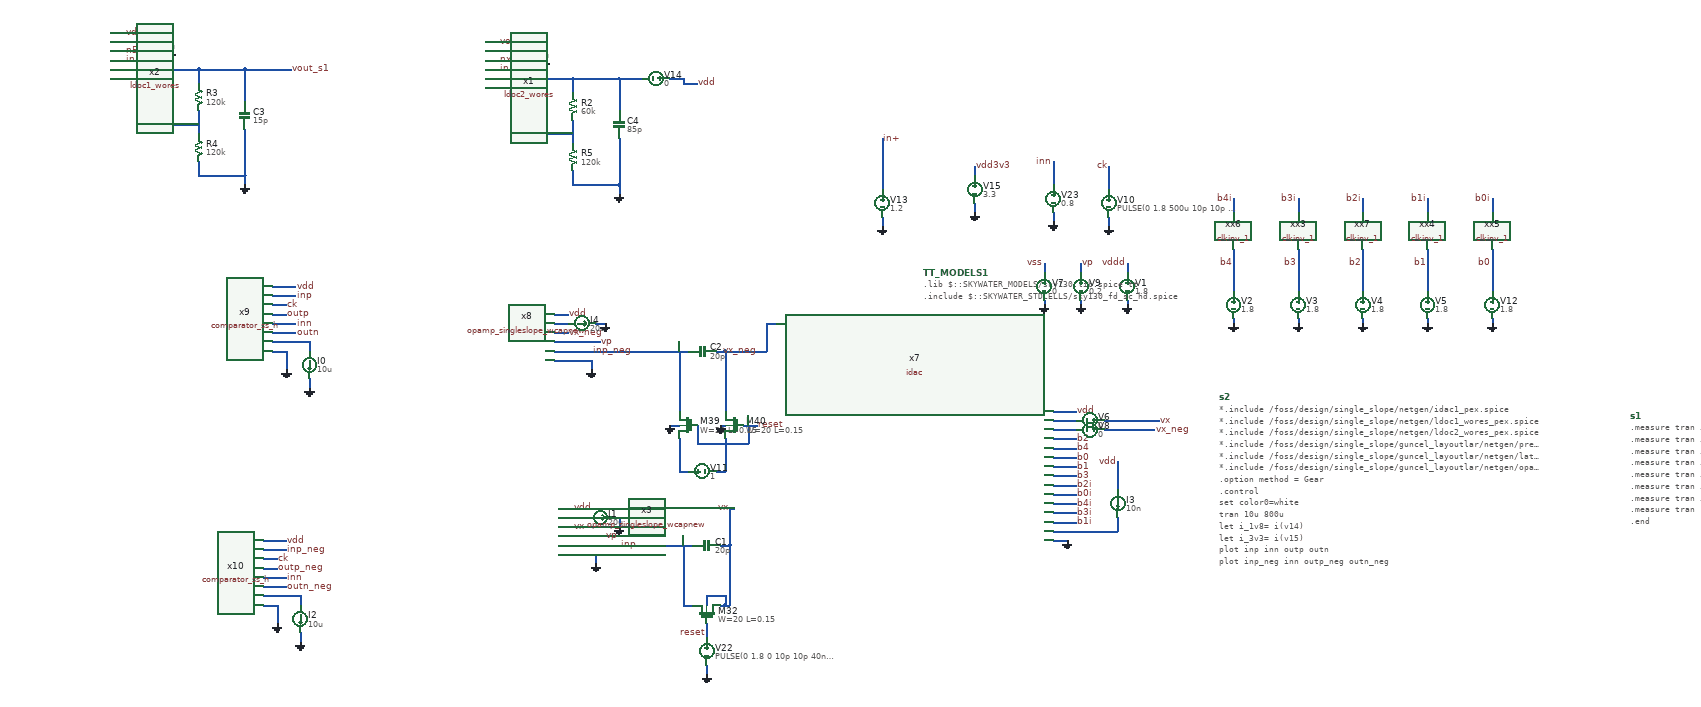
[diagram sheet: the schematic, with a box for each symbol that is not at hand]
v {xschem version=3.0.0 file_version=1.2 }
G {}
K {}
V {}
S {}
E {}
N 2600 -880 2600 -870 {
lab=GND}
N 2600 -960 2600 -940 {
lab=vddd}
N 2500 -880 2500 -870 {
lab=GND}
N 2500 -960 2500 -940 {
lab=vp}
N 2830 -990 2830 -960 {
lab=b4}
N 3250 -990 3250 -960 {
lab=b1}
N 3110 -990 3110 -960 {
lab=b2}
N 2970 -990 2970 -960 {
lab=b3}
N 3390 -990 3390 -960 {
lab=b0}
N 2830 -1100 2830 -1070 {
lab=b4i}
N 2970 -1100 2970 -1070 {
lab=b3i}
N 3110 -1100 3110 -1070 {
lab=b2i}
N 3250 -1100 3250 -1070 {
lab=b1i}
N 3390 -1100 3390 -1070 {
lab=b0i}
N 2420 -880 2420 -870 {
lab=GND}
N 2420 -960 2420 -940 {
lab=vss}
N 2830 -840 2830 -830 {
lab=GND}
N 2830 -910 2830 -900 {
lab=b4}
N 2970 -840 2970 -830 {
lab=GND}
N 3110 -840 3110 -830 {
lab=GND}
N 3250 -840 3250 -830 {
lab=GND}
N 3390 -840 3390 -830 {
lab=GND}
N 3110 -910 3110 -900 {
lab=b2}
N 2970 -910 2970 -900 {
lab=b3}
N 3390 -910 3390 -900 {
lab=b0}
N 3110 -920 3110 -910 {
lab=b2}
N 2970 -920 2970 -910 {
lab=b3}
N 3390 -920 3390 -910 {
lab=b0}
N 2830 -960 2830 -930 {
lab=b4}
N 3250 -960 3250 -930 {
lab=b1}
N 3110 -930 3110 -920 {
lab=b2}
N 2970 -930 2970 -920 {
lab=b3}
N 3110 -960 3110 -930 {
lab=b2}
N 2970 -960 2970 -930 {
lab=b3}
N 3390 -930 3390 -920 {
lab=b0}
N 3390 -960 3390 -930 {
lab=b0}
N 3250 -930 3250 -900 {
lab=b1}
N 2830 -930 2830 -910 {
lab=b4}
N 1720 -350 1740 -350 {
lab=vx}
N 1740 -430 1740 -350 {
lab=vx}
N 1580 -350 1660 -350 {
lab=inp}
N 1640 -220 1660 -220 {
lab=inp}
N 1640 -350 1640 -220 {
lab=inp}
N 1720 -220 1730 -220 {
lab=vx}
N 1730 -220 1740 -220 {
lab=vx}
N 1740 -350 1740 -220 {
lab=vx}
N 1690 -240 1690 -220 {
lab=vx}
N 1690 -240 1730 -240 {
lab=vx}
N 1730 -240 1730 -220 {
lab=vx}
N 1690 -180 1690 -150 {
lab=reset}
N 1690 -90 1690 -70 {
lab=GND}
N 1480 -350 1580 -350 {
lab=inp}
N 1370 -430 1400 -430 {
lab=vdd}
N 1370 -390 1400 -390 {
lab=vx}
N 1370 -370 1450 -370 {
lab=vp}
N 1370 -350 1390 -350 {
lab=inp}
N 1370 -330 1450 -330 {
lab=GND}
N 1450 -330 1450 -310 {
lab=GND}
N 1390 -350 1480 -350 {
lab=inp}
N 1450 -370 1470 -370 {
lab=vp}
N 1500 -410 1500 -390 {
lab=GND}
N 1370 -410 1430 -410 {
lab=#net1}
N 1490 -410 1500 -410 {
lab=GND}
N 1710 -770 1730 -770 {
lab=vx_neg}
N 1570 -770 1650 -770 {
lab=inp_neg}
N 1630 -770 1630 -640 {
lab=inp_neg}
N 1730 -770 1730 -640 {
lab=vx_neg}
N 1470 -770 1570 -770 {
lab=inp_neg}
N 1360 -830 1390 -830 {
lab=#net2}
N 1360 -810 1390 -810 {
lab=vx_neg}
N 1360 -790 1440 -790 {
lab=vp}
N 1360 -770 1380 -770 {
lab=inp_neg}
N 1360 -750 1440 -750 {
lab=GND}
N 1440 -750 1440 -730 {
lab=GND}
N 1380 -770 1470 -770 {
lab=inp_neg}
N 1440 -790 1460 -790 {
lab=vp}
N 1630 -510 1650 -510 {
lab=#net3}
N 1710 -510 1730 -510 {
lab=#net4}
N 1630 -580 1630 -510 {
lab=#net3}
N 1730 -580 1730 -510 {
lab=#net4}
N 1610 -610 1630 -610 {
lab=GND}
N 1720 -610 1730 -610 {
lab=GND}
N 1770 -610 1800 -610 {
lab=reset}
N 1670 -610 1670 -570 {
lab=reset}
N 1670 -570 1780 -570 {
lab=reset}
N 1780 -610 1780 -570 {
lab=reset}
N 1730 -770 1800 -770 {
lab=vx_neg}
N 1360 -850 1390 -850 {
lab=vdd}
N 1450 -830 1470 -830 {
lab=GND}
N 2440 -640 2490 -640 {
lab=vdd}
N 2440 -620 2490 -620 {
lab=#net5}
N 2440 -360 2470 -360 {
lab=GND}
N 2440 -580 2490 -580 {
lab=b2}
N 2440 -560 2490 -560 {
lab=b4}
N 2440 -540 2490 -540 {
lab=b0}
N 2440 -520 2490 -520 {
lab=b1}
N 2440 -500 2490 -500 {
lab=b3}
N 2440 -480 2490 -480 {
lab=b2i}
N 2440 -460 2490 -460 {
lab=b0i}
N 2440 -440 2490 -440 {
lab=b4i}
N 2440 -420 2490 -420 {
lab=b3i}
N 2440 -400 2490 -400 {
lab=b1i}
N 2440 -380 2490 -380 {
lab=#net6}
N 2580 -510 2580 -470 {
lab=vdd}
N 2580 -530 2580 -510 {
lab=vdd}
N 2490 -380 2580 -380 {
lab=#net6}
N 2560 -620 2590 -620 {
lab=vx}
N 2550 -620 2560 -620 {
lab=vx}
N 2550 -600 2590 -600 {
lab=vx_neg}
N 2440 -600 2490 -600 {
lab=#net7}
N 2560 -1060 2560 -1040 {
lab=GND}
N 2560 -1170 2560 -1120 {
lab=ck}
N 2440 -1070 2440 -1050 {
lab=GND}
N 2440 -1180 2440 -1130 {
lab=inn}
N 1740 -430 1750 -430 {
lab=vx}
N 1800 -770 1820 -770 {
lab=vx_neg}
N 1820 -830 1820 -770 {
lab=vx_neg}
N 1820 -830 1840 -830 {
lab=vx_neg}
N 2580 -410 2580 -380 {
lab=#net6}
N 780 -770 780 -730 {
lab=GND}
N 750 -890 800 -890 {
lab=inp}
N 750 -830 800 -830 {
lab=inn}
N 750 -810 800 -810 {
lab=outn}
N 750 -870 780 -870 {
lab=ck}
N 750 -850 780 -850 {
lab=outp}
N 750 -910 800 -910 {
lab=vdd}
N 750 -770 780 -770 {
lab=GND}
N 830 -790 830 -770 {
lab=#net8}
N 830 -710 830 -690 {
lab=GND}
N 750 -790 830 -790 {
lab=#net8}
N 760 -220 760 -180 {
lab=GND}
N 730 -340 780 -340 {
lab=inp_neg}
N 730 -280 780 -280 {
lab=inn}
N 730 -260 780 -260 {
lab=outn_neg}
N 730 -320 760 -320 {
lab=ck}
N 730 -300 760 -300 {
lab=outp_neg}
N 730 -360 780 -360 {
lab=vdd}
N 730 -220 760 -220 {
lab=GND}
N 810 -240 810 -220 {
lab=#net9}
N 810 -160 810 -140 {
lab=GND}
N 730 -240 810 -240 {
lab=#net9}
N 2070 -1140 2070 -1120 {
lab=in+}
N 2070 -1060 2070 -1040 {
lab=GND}
N 2070 -1150 2070 -1140 {
lab=in+}
N 2070 -1160 2070 -1150 {
lab=in+}
N 2070 -1230 2070 -1220 {
lab=in+}
N 2070 -1220 2070 -1160 {
lab=in+}
N 2270 -1090 2270 -1070 {
lab=GND}
N 2270 -1170 2270 -1150 {
lab=vdd3v3}
N 2590 -620 2670 -620 {
lab=vx}
N 2590 -600 2660 -600 {
lab=vx_neg}
N 690 -1320 690 -1310 {
lab=vout_s1}
N 690 -1150 690 -1130 {
lab=GND}
N 590 -1290 590 -1240 {
lab=n5}
N 590 -1380 590 -1350 {
lab=vout_s1}
N 590 -1380 690 -1380 {
lab=vout_s1}
N 690 -1380 690 -1320 {
lab=vout_s1}
N 690 -1250 690 -1150 {
lab=GND}
N 590 -1150 690 -1150 {
lab=GND}
N 590 -1180 590 -1150 {
lab=GND}
N 690 -1380 790 -1380 {
lab=vout_s1}
N 530 -1260 590 -1260 {
lab=n5}
N 550 -1380 590 -1380 {
lab=vout_s1}
N 400 -1460 430 -1460 {
lab=vdd3v3}
N 400 -1420 430 -1420 {
lab=n5}
N 400 -1380 420 -1380 {
lab=vout_s1}
N 400 -1360 480 -1360 {
lab=GND}
N 480 -1360 480 -1340 {
lab=GND}
N 530 -1440 530 -1420 {
lab=GND}
N 400 -1440 460 -1440 {
lab=#net10}
N 520 -1440 530 -1440 {
lab=GND}
N 400 -1400 430 -1400 {
lab=in+}
N 420 -1380 430 -1380 {
lab=vout_s1}
N 430 -1380 550 -1380 {
lab=vout_s1}
N 1500 -1300 1500 -1290 {
lab=#net11}
N 1500 -1130 1500 -1110 {
lab=GND}
N 1400 -1270 1400 -1220 {
lab=nx}
N 1400 -1360 1400 -1330 {
lab=#net11}
N 1400 -1360 1500 -1360 {
lab=#net11}
N 1500 -1360 1500 -1300 {
lab=#net11}
N 1500 -1230 1500 -1130 {
lab=GND}
N 1400 -1130 1500 -1130 {
lab=GND}
N 1400 -1160 1400 -1130 {
lab=GND}
N 1340 -1240 1400 -1240 {
lab=nx}
N 1360 -1360 1400 -1360 {
lab=#net11}
N 1210 -1440 1240 -1440 {
lab=vout_s1}
N 1210 -1400 1240 -1400 {
lab=nx}
N 1210 -1360 1230 -1360 {
lab=#net11}
N 1210 -1340 1290 -1340 {
lab=GND}
N 1290 -1340 1290 -1320 {
lab=GND}
N 1340 -1420 1340 -1400 {
lab=GND}
N 1210 -1420 1270 -1420 {
lab=#net12}
N 1330 -1420 1340 -1420 {
lab=GND}
N 1210 -1380 1240 -1380 {
lab=in+}
N 1230 -1360 1240 -1360 {
lab=#net11}
N 1240 -1360 1360 -1360 {
lab=#net11}
N 1500 -1360 1550 -1360 {
lab=#net11}
N 1610 -1360 1640 -1360 {
lab=vdd}
N 1640 -1360 1640 -1350 {
lab=vdd}
N 1640 -1350 1670 -1350 {
lab=vdd}
C {devices/code_shown.sym} 2800 -670 0 0 {name=s2 only_toplevel=false value="


*.include /foss/design/single_slope/netgen/idac1_pex.spice
*.include /foss/design/single_slope/netgen/ldoc1_wores_pex.spice
*.include /foss/design/single_slope/netgen/ldoc2_wores_pex.spice
*.include /foss/design/single_slope/guncel_layoutlar/netgen/preamp_singleslope_new_pex.spice
*.include /foss/design/single_slope/guncel_layoutlar/netgen/latch_singleslope_new_pex.spice
*.include /foss/design/single_slope/guncel_layoutlar/netgen/opamp_singleslope_addcap_pex.spice
.option method = Gear

.control
set color0=white

tran 10u 800u
let i_1v8= i(v14)
let i_3v3= i(v15)
plot inp inn outp outn
plot inp_neg inn outp_neg outn_neg
plot i_1v8 i_3v3

.endc
.end
"
}
C {devices/vsource.sym} 2600 -910 0 0 {name=V1 value=1.8}
C {devices/gnd.sym} 2600 -870 0 1 {name=l6 lab=GND}
C {devices/lab_pin.sym} 2600 -960 0 0 {name=l7 sig_type=std_logic lab=vddd}
C {devices/code.sym} 2160 -940 0 0 {name=TT_MODELS1
only_toplevel=true
format="tcleval(@value )"
value=".lib $::SKYWATER_MODELS/sky130.lib.spice tt
.include $::SKYWATER_STDCELLS/sky130_fd_sc_hd.spice
"
spice_ignore=false
place=header}
C {devices/vsource.sym} 2500 -910 0 0 {name=V9 value=0.2}
C {devices/gnd.sym} 2500 -870 0 1 {name=l5 lab=GND}
C {pdk/sky130A/libs.tech/xschem/sky130_stdcells/clkinv_1.sym} 2830 -1030 3 0 {name=xx6 VGND=vss VNB=vss VPB=vddd VPWR=vddd prefix=sky130_fd_sc_hd__ }
C {devices/lab_pin.sym} 2830 -1100 0 0 {name=p6 sig_type=std_logic lab=b4i
}
C {devices/lab_pin.sym} 2970 -1100 0 0 {name=p7 sig_type=std_logic lab=b3i
}
C {devices/lab_pin.sym} 3110 -1100 0 0 {name=p8 sig_type=std_logic lab=b2i
}
C {devices/lab_pin.sym} 3250 -1100 0 0 {name=p9 sig_type=std_logic lab=b1i
}
C {devices/lab_pin.sym} 3390 -1100 0 0 {name=p16 sig_type=std_logic lab=b0i
}
C {pdk/sky130A/libs.tech/xschem/sky130_stdcells/clkinv_1.sym} 3250 -1030 3 0 {name=xx4 VGND=vss VNB=vss VPB=vddd VPWR=vddd prefix=sky130_fd_sc_hd__ }
C {pdk/sky130A/libs.tech/xschem/sky130_stdcells/clkinv_1.sym} 3390 -1030 3 0 {name=xx5 VGND=vss VNB=vss VPB=vddd VPWR=vddd prefix=sky130_fd_sc_hd__ }
C {devices/vsource.sym} 2420 -910 0 0 {name=V7 value=0}
C {devices/gnd.sym} 2420 -870 0 1 {name=l53 lab=GND}
C {devices/lab_pin.sym} 2420 -960 0 0 {name=l54 sig_type=std_logic lab=vss}
C {devices/vsource.sym} 2830 -870 0 0 {name=V2 value= 1.8
*"PULSE(1.8 0 0 1n 1n 4096u 8192u)" savecurrent=false}
C {devices/gnd.sym} 2830 -830 0 1 {name=l4 lab=GND}
C {devices/gnd.sym} 2970 -830 0 1 {name=l24 lab=GND}
C {devices/gnd.sym} 3110 -830 0 1 {name=l25 lab=GND}
C {devices/gnd.sym} 3250 -830 0 1 {name=l26 lab=GND}
C {devices/gnd.sym} 3390 -830 0 1 {name=l27 lab=GND}
C {devices/lab_pin.sym} 2830 -960 0 0 {name=p11 sig_type=std_logic lab=b4
}
C {devices/vsource.sym} 2970 -870 0 0 {name=V3 value= 1.8
*"PULSE(1.8 0 0 1n 1n 2048u 4096u)" savecurrent=false}
C {devices/vsource.sym} 3110 -870 0 0 {name=V4 value=1.8
*"PULSE(1.8 0 0 1n 1n 1024u 2048u)" savecurrent=false}
C {devices/vsource.sym} 3250 -870 0 0 {name=V5 value=1.8
*"PULSE(1.8 0 0 1n 1n 512u 1024u)" savecurrent=false}
C {devices/vsource.sym} 3390 -870 0 0 {name=V12 value=1.8
*"PULSE(1.8 0 0 1n 1n 256u 512u)" savecurrent=false}
C {devices/lab_pin.sym} 3250 -960 0 0 {name=p12 sig_type=std_logic lab=b1
}
C {devices/lab_pin.sym} 2970 -960 0 0 {name=p13 sig_type=std_logic lab=b3
}
C {devices/lab_pin.sym} 3110 -960 0 0 {name=p14 sig_type=std_logic lab=b2
}
C {devices/lab_pin.sym} 3390 -960 0 0 {name=p15 sig_type=std_logic lab=b0
}
C {devices/lab_pin.sym} 2500 -960 2 0 {name=l59 sig_type=std_logic lab=vp}
C {devices/capa.sym} 1690 -350 1 0 {name=C1
m=1
value=20p
footprint=1206
device="ceramic capacitor"}
C {devices/lab_pin.sym} 1740 -430 1 0 {name=l80 sig_type=std_logic lab=vx}
C {pdk/sky130A/libs.tech/xschem/sky130_fd_pr/nfet_01v8.sym} 1690 -200 3 0 {name=M32
L=0.15
W=20
nf=1 
mult=2
ad="'int((nf+1)/2) * W/nf * 0.29'" 
pd="'2*int((nf+1)/2) * (W/nf + 0.29)'"
as="'int((nf+2)/2) * W/nf * 0.29'" 
ps="'2*int((nf+2)/2) * (W/nf + 0.29)'"
nrd="'0.29 / W'" nrs="'0.29 / W'"
sa=0 sb=0 sd=0
model=nfet_01v8
spiceprefix=X
}
C {devices/vsource.sym} 1690 -120 0 0 {name=V22 value="PULSE(0 1.8 0 10p 10p 40n 256.04u)"}
C {devices/gnd.sym} 1690 -70 0 0 {name=l81 lab=GND}
C {devices/lab_pin.sym} 1400 -430 2 0 {name=l82 sig_type=std_logic lab=vdd}
C {devices/lab_pin.sym} 1690 -160 0 0 {name=l83 sig_type=std_logic lab=reset}
C {devices/lab_pin.sym} 1400 -390 2 0 {name=l84 sig_type=std_logic lab=vx}
C {devices/gnd.sym} 1450 -310 0 0 {name=l85 lab=GND}
C {devices/lab_pin.sym} 1540 -350 1 0 {name=l86 sig_type=std_logic lab=inp}
C {devices/isource.sym} 1460 -410 3 0 {name=I1 value=20u}
C {devices/gnd.sym} 1500 -390 0 0 {name=l87 lab=GND}
C {design/single_slope/opamp_singleslope_wcapnew.sym} 1220 -380 0 0 {name=x3}
C {devices/lab_pin.sym} 1470 -370 0 1 {name=l88 sig_type=std_logic lab=vp}
C {devices/capa.sym} 1680 -770 1 0 {name=C2
m=1
value=20p
footprint=1206
device="ceramic capacitor"}
C {devices/lab_pin.sym} 1800 -770 1 0 {name=l97 sig_type=std_logic lab=vx_neg}
C {devices/lab_pin.sym} 1390 -850 2 0 {name=l98 sig_type=std_logic lab=vdd}
C {devices/lab_pin.sym} 1390 -810 2 0 {name=l99 sig_type=std_logic lab=vx_neg}
C {devices/gnd.sym} 1440 -730 0 0 {name=l100 lab=GND}
C {devices/lab_pin.sym} 1530 -770 1 0 {name=l101 sig_type=std_logic lab=inp_neg}
C {devices/vsource.sym} 1680 -510 3 0 {name=V11 value=1}
C {devices/lab_pin.sym} 1800 -610 0 1 {name=l102 sig_type=std_logic lab=reset}
C {pdk/sky130A/libs.tech/xschem/sky130_fd_pr/nfet_01v8.sym} 1650 -610 2 0 {name=M39
L=0.15
W=20
nf=1 
mult=2
ad="'int((nf+1)/2) * W/nf * 0.29'" 
pd="'2*int((nf+1)/2) * (W/nf + 0.29)'"
as="'int((nf+2)/2) * W/nf * 0.29'" 
ps="'2*int((nf+2)/2) * (W/nf + 0.29)'"
nrd="'0.29 / W'" nrs="'0.29 / W'"
sa=0 sb=0 sd=0
model=nfet_01v8
spiceprefix=X
}
C {pdk/sky130A/libs.tech/xschem/sky130_fd_pr/nfet_01v8.sym} 1750 -610 2 0 {name=M40
L=0.15
W=20
nf=1 
mult=2
ad="'int((nf+1)/2) * W/nf * 0.29'" 
pd="'2*int((nf+1)/2) * (W/nf + 0.29)'"
as="'int((nf+2)/2) * W/nf * 0.29'" 
ps="'2*int((nf+2)/2) * (W/nf + 0.29)'"
nrd="'0.29 / W'" nrs="'0.29 / W'"
sa=0 sb=0 sd=0
model=nfet_01v8
spiceprefix=X
}
C {devices/gnd.sym} 1610 -610 0 0 {name=l103 lab=GND}
C {devices/gnd.sym} 1720 -610 0 0 {name=l104 lab=GND}
C {devices/lab_pin.sym} 1460 -790 0 1 {name=l105 sig_type=std_logic lab=vp}
C {design/single_slope/opamp_singleslope_wcapnew.sym} 1210 -800 0 0 {name=x8}
C {devices/isource.sym} 1420 -830 3 0 {name=I4 value=20u}
C {devices/gnd.sym} 1470 -830 0 0 {name=l106 lab=GND}
C {devices/lab_pin.sym} 2490 -640 2 0 {name=l76 sig_type=std_logic lab=vdd}
C {devices/lab_pin.sym} 2670 -620 2 0 {name=l79 sig_type=std_logic lab=vx}
C {devices/lab_pin.sym} 2660 -600 2 0 {name=l107 sig_type=std_logic lab=vx_neg}
C {devices/lab_pin.sym} 2490 -580 2 0 {name=l109 sig_type=std_logic lab=b2}
C {devices/lab_pin.sym} 2490 -560 2 0 {name=l110 sig_type=std_logic lab=b4}
C {devices/lab_pin.sym} 2490 -540 2 0 {name=l111 sig_type=std_logic lab=b0}
C {devices/lab_pin.sym} 2490 -520 2 0 {name=l112 sig_type=std_logic lab=b1}
C {devices/lab_pin.sym} 2490 -500 2 0 {name=l113 sig_type=std_logic lab=b3}
C {devices/lab_pin.sym} 2490 -480 2 0 {name=l114 sig_type=std_logic lab=b2i}
C {devices/lab_pin.sym} 2490 -460 2 0 {name=l115 sig_type=std_logic lab=b0i}
C {devices/lab_pin.sym} 2490 -440 2 0 {name=l116 sig_type=std_logic lab=b4i}
C {devices/lab_pin.sym} 2490 -420 2 0 {name=l117 sig_type=std_logic lab=b3i}
C {devices/lab_pin.sym} 2490 -400 2 0 {name=l118 sig_type=std_logic lab=b1i}
C {devices/isource.sym} 2580 -440 0 0 {name=I3 value=10n}
C {devices/lab_pin.sym} 2580 -530 0 0 {name=l119 sig_type=std_logic lab=vdd}
C {design/single_slope/idac.sym} 2290 -500 0 0 {name=x7}
C {devices/gnd.sym} 2470 -360 0 0 {name=l15 lab=GND}
C {devices/vsource.sym} 2560 -1090 0 0 {name=V10 value="PULSE(0 1.8 500u 10p 10p .5u 1u)"
}
C {devices/gnd.sym} 2560 -1040 0 0 {name=l123 lab=GND}
C {devices/lab_pin.sym} 2560 -1170 0 0 {name=l124 sig_type=std_logic lab=ck}
C {devices/vsource.sym} 2440 -1100 0 0 {name=V23 value=0.8}
C {devices/gnd.sym} 2440 -1050 0 0 {name=l125 lab=GND}
C {devices/lab_pin.sym} 2440 -1180 0 0 {name=l126 sig_type=std_logic lab=inn}
C {devices/vsource.sym} 2520 -620 1 0 {name=V6 value=0}
C {devices/vsource.sym} 2520 -600 1 0 {name=V8 value=0}
C {devices/gnd.sym} 780 -730 0 0 {name=l1 lab=GND}
C {devices/lab_pin.sym} 800 -910 0 1 {name=l2 sig_type=std_logic lab=vdd}
C {devices/lab_pin.sym} 780 -870 0 1 {name=l3 sig_type=std_logic lab=ck}
C {devices/lab_pin.sym} 800 -890 0 1 {name=l108 sig_type=std_logic lab=inp}
C {devices/lab_pin.sym} 800 -830 0 1 {name=l8 sig_type=std_logic lab=inn}
C {devices/lab_pin.sym} 780 -850 0 1 {name=l9 sig_type=std_logic lab=outp}
C {devices/lab_pin.sym} 800 -810 0 1 {name=l10 sig_type=std_logic lab=outn}
C {devices/isource.sym} 830 -740 0 0 {name=I0 value=10u}
C {devices/gnd.sym} 830 -690 0 0 {name=l11 lab=GND}
C {design/single_slope/comparator_ss_h.sym} 600 -840 0 0 {name=x9}
C {devices/gnd.sym} 760 -180 0 0 {name=l19 lab=GND}
C {devices/lab_pin.sym} 780 -360 0 1 {name=l20 sig_type=std_logic lab=vdd}
C {devices/lab_pin.sym} 760 -320 0 1 {name=l21 sig_type=std_logic lab=ck}
C {devices/lab_pin.sym} 780 -340 0 1 {name=l22 sig_type=std_logic lab=inp_neg}
C {devices/lab_pin.sym} 780 -280 0 1 {name=l12 sig_type=std_logic lab=inn}
C {devices/lab_pin.sym} 760 -300 0 1 {name=l13 sig_type=std_logic lab=outp_neg}
C {devices/lab_pin.sym} 780 -260 0 1 {name=l30 sig_type=std_logic lab=outn_neg}
C {devices/isource.sym} 810 -190 0 0 {name=I2 value=10u}
C {devices/gnd.sym} 810 -140 0 0 {name=l31 lab=GND}
C {design/single_slope/comparator_ss_h.sym} 580 -290 0 0 {name=x10}
C {pdk/sky130A/libs.tech/xschem/sky130_stdcells/clkinv_1.sym} 3110 -1030 3 0 {name=xx7 VGND=vss VNB=vss VPB=vddd VPWR=vddd prefix=sky130_fd_sc_hd__ }
C {pdk/sky130A/libs.tech/xschem/sky130_stdcells/clkinv_1.sym} 2970 -1030 3 0 {name=xx3 VGND=vss VNB=vss VPB=vddd VPWR=vddd prefix=sky130_fd_sc_hd__ }
C {devices/vsource.sym} 2070 -1090 0 0 {name=V13 value=1.2}
C {devices/gnd.sym} 2070 -1040 0 0 {name=l14 lab=GND}
C {devices/lab_pin.sym} 2070 -1230 2 0 {name=l16 sig_type=std_logic lab=in+}
C {devices/vsource.sym} 2270 -1120 0 0 {name=V15 value=3.3}
C {devices/gnd.sym} 2270 -1070 0 0 {name=l34 lab=GND}
C {devices/lab_pin.sym} 2270 -1170 0 1 {name=l35 sig_type=std_logic lab=vdd3v3}
C {devices/code_shown.sym} 3690 -630 0 0 {name=s1 only_toplevel=false value="

.measure tran ipp1 PP i(v15) from=517u to=518u
.measure tran ipp2 PP i(v15) from=532u to=533u
.measure tran ipp3 PP i(v15) from=562u to=563u
.measure tran ipp4 PP i(v15) from=612u to=613u
.measure tran ipp5 PP i(v15) from=682u to=683u
.measure tran ipp6 PP i(v15) from=732u to=733u
.measure tran iavg AVG i(v15) from=513u to=767u
.measure tran ravg AVG zort from=1u to=255u
.end
"
}
C {devices/capa.sym} 690 -1280 0 0 {name=C3
m=1
value=15p
footprint=1206
device="ceramic capacitor"}
C {devices/gnd.sym} 690 -1130 0 0 {name=l17 lab=GND}
C {devices/res.sym} 590 -1320 0 0 {name=R3
value=120k
footprint=1206
device=resistor
m=1}
C {devices/res.sym} 590 -1210 0 0 {name=R4
value=120k
footprint=1206
device=resistor
m=1}
C {devices/lab_pin.sym} 530 -1260 0 0 {name=l18 sig_type=std_logic lab=n5}
C {devices/lab_pin.sym} 790 -1380 0 1 {name=l23 sig_type=std_logic lab=vout_s1}
C {devices/lab_pin.sym} 430 -1460 2 0 {name=l28 sig_type=std_logic lab=vdd3v3}
C {devices/lab_pin.sym} 430 -1420 2 0 {name=l29 sig_type=std_logic lab=n5}
C {devices/gnd.sym} 480 -1340 0 0 {name=l32 lab=GND}
C {devices/lab_pin.sym} 430 -1400 2 0 {name=l33 sig_type=std_logic lab=in+}
C {devices/isource.sym} 490 -1440 3 0 {name=I5 value=15u}
C {devices/gnd.sym} 530 -1420 0 0 {name=l36 lab=GND}
C {design/ldo/ldoc1_wores.sym} 250 -1410 0 0 {name=x2}
C {devices/capa.sym} 1500 -1260 0 0 {name=C4
m=1
value=85p
footprint=1206
device="ceramic capacitor"}
C {devices/gnd.sym} 1500 -1110 0 0 {name=l37 lab=GND}
C {devices/res.sym} 1400 -1300 0 0 {name=R2
value=60k
footprint=1206
device=resistor
m=1}
C {devices/res.sym} 1400 -1190 0 0 {name=R5
value=120k
footprint=1206
device=resistor
m=1}
C {devices/lab_pin.sym} 1340 -1240 0 0 {name=l38 sig_type=std_logic lab=nx}
C {devices/lab_pin.sym} 1670 -1350 0 1 {name=l39 sig_type=std_logic lab=vdd}
C {devices/lab_pin.sym} 1240 -1440 2 0 {name=l40 sig_type=std_logic lab=vout_s1}
C {devices/lab_pin.sym} 1240 -1400 2 0 {name=l41 sig_type=std_logic lab=nx}
C {devices/gnd.sym} 1290 -1320 0 0 {name=l42 lab=GND}
C {devices/lab_pin.sym} 1240 -1380 2 0 {name=l43 sig_type=std_logic lab=in+}
C {devices/isource.sym} 1300 -1420 3 0 {name=I6 value=15u}
C {devices/gnd.sym} 1340 -1400 0 0 {name=l44 lab=GND}
C {design/ldo/ldoc2_wores.sym} 1060 -1390 0 0 {name=x1}
C {devices/vsource.sym} 1580 -1360 1 0 {name=V14 value=0}
